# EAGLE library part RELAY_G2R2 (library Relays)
RELAY 2 x switch, Omron

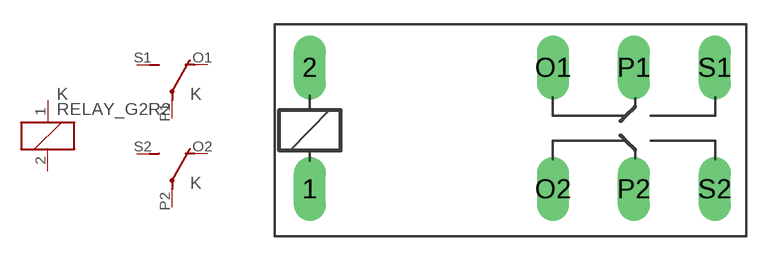
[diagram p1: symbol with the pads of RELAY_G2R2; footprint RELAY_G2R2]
Designator prefix K; gates 1=RELAY_K 2=RELAY_U 3=RELAY_U

## RELAY_G2R2 (MF: OMRON COMPONENTS USA; MPN: G2R-2-DC6; OC_FARNELL: unknown; OC_NEWARK: 89C5317)  [RELAY_G2R2]
1  1:1  pas
2  1:2  pas
O1  2:O  pas
O2  3:O  pas
P1  2:P  pas
P2  3:P  pas
S1  2:S  pas
S2  3:S  pas

## Footprint RELAY_G2R2 (pad centres in mm)
RELAY 2 x switch, Omron
drill 1.321 long: 1 -2.54,-3.683; 2 -2.54,3.81; O1 12.471,3.81; O2 12.471,-3.683; P1 17.45,3.81; P2 17.45,-3.683; S1 22.454,3.81; S2 22.454,-3.683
